# LEF file generated by Abstract Generator version 5.5.10 on Jul 30 14:47:58 2004
#
# Contains LEF for all bins.
# Options:   [x] Antenna
#            [x] Geometry
#            [x] Technology
VERSION 5.4 ;
NAMESCASESENSITIVE ON ;
BUSBITCHARS "[]" ;
DIVIDERCHAR "/" ;
UNITS
  DATABASE MICRONS 1000 ;
END UNITS

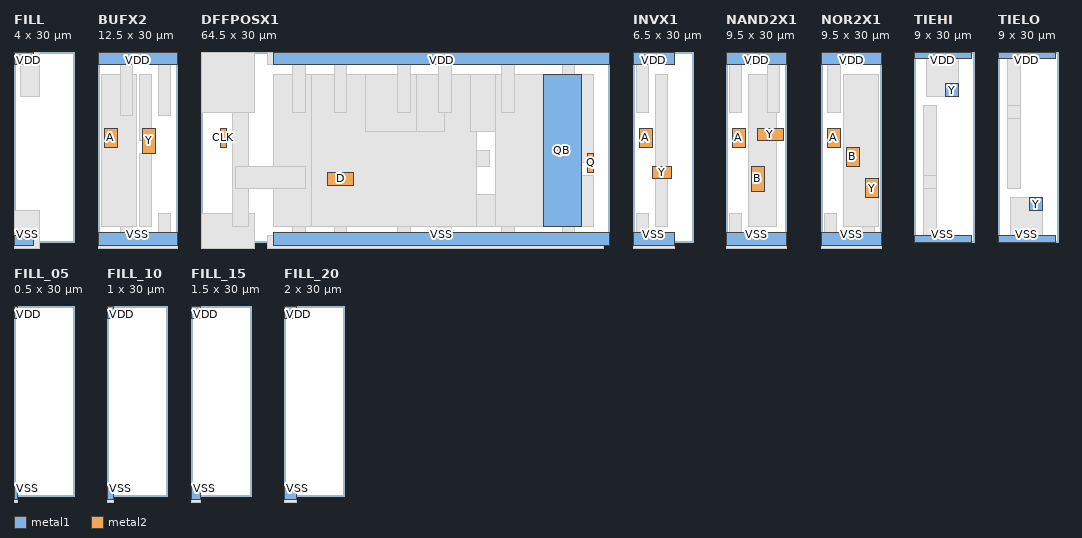
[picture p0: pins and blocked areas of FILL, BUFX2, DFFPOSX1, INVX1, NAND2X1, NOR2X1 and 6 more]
MACRO FILL
  CLASS CORE ;
  SOURCE USER ;
  ORIGIN 0 0 ;
  SIZE 4.0 BY 30.000 ;
  SYMMETRY Y ;
  SITE unit ;

  PIN VDD    DIRECTION INOUT ;
    USE POWER ;
    PORT
      LAYER metal1 ;
        RECT 0 28 3 30 ;
    END
  END VDD
  PIN VSS    DIRECTION INOUT ;
    USE GROUND ;
    PORT
      LAYER metal1 ;
        RECT 0 -0.5 3 1 ;
    END
  END VSS
  OBS
      LAYER metal1 ;
        RECT 0 -1 4 5 ;
        RECT 1 23 4 30 ;
  END
END FILL

MACRO BUFX2
  CLASS CORE ;
  SOURCE USER ;
  ORIGIN 0 0 ;
  SIZE 12.5 BY 30.000 ;
  SYMMETRY Y ;
  SITE unit ;

  PIN VDD    DIRECTION INOUT ;
    USE POWER ;
    PORT
      LAYER metal1 ;
        RECT 0.000 28.000 12.500 30.000 ;
    END
  END VDD
  PIN VSS    DIRECTION INOUT ;
    USE GROUND ;
    PORT
      LAYER metal1 ;
        RECT 0.000 -0.500 12.500 1.500 ;
    END
  END VSS
  PIN A    DIRECTION INPUT ;
    USE SIGNAL ;
    PORT
      LAYER metal2 ;
        RECT 1.000 15.000 3.000 18.000 ;
    END
  END A
  PIN Y    DIRECTION OUTPUT ;
    USE SIGNAL ;
    PORT
      LAYER metal2 ;
        RECT 7.000 14.000 9.000 18.000 ;
    END
  END Y
  OBS
      LAYER metal1 ;
        RECT 0 -1 12.5 1 ;
        RECT 3.5 1.5 5.5 4.5 ;
        RECT 9.5 1.5 11.5 4.5 ;
        RECT 6.5 2.5 8.5 14 ;
        RECT 0.5 2.5 6 26.5 ;
        RECT 6.5 16 8.5 26.5 ;
        RECT 3.5 20 5.5 28 ;
        RECT 9.5 20 11.5 28 ;
  END
END BUFX2

MACRO DFFPOSX1
  CLASS CORE ;
  SOURCE USER ;
  ORIGIN 0 0 ;
  SIZE 64.5 BY 30.000 ;
  SYMMETRY Y ;
  SITE unit ;

  PIN VDD    DIRECTION INOUT ;
    USE POWER ;
    PORT
      LAYER metal1 ;
        RECT 11.500 28.000 64.500 30.000 ;
    END
  END VDD
  PIN VSS    DIRECTION INOUT ;
    USE GROUND ;
    PORT
      LAYER metal1 ;
        RECT 11.500 -0.500 64.500 1.500 ;
    END
  END VSS
  PIN CLK    DIRECTION INPUT ;
    USE SIGNAL ;
    PORT
      LAYER metal2 ;
        RECT 3.000 15.000 4.000 18.000 ;
    END
  END CLK
  PIN D    DIRECTION INPUT ;
    USE SIGNAL ;
    PORT
      LAYER metal2 ;
        RECT 20.000 9.000 24.000 11.000 ;
    END
  END D
  PIN Q    DIRECTION OUTPUT ;
    USE SIGNAL ;
    PORT
      LAYER metal2 ;
        RECT 61.000 11.000 62.000 14.000 ;
    END
  END Q
  PIN QB
    DIRECTION OUTPUT ;
    USE SIGNAL ;
    PORT
      LAYER metal1 ;
        RECT 54.000 2.5 60.000 26.5 ;
    END
  END QB
  OBS
      LAYER metal1 ;
        RECT 10.5 -1 63.5 1 ;
        RECT 57 1.5 59 2.5 ;
        RECT 0 -1 8.5 4.5 ;
        RECT 14.5 1.5 16.5 4.5 ;
        RECT 21 1.5 23 4.5 ;
        RECT 31 1.5 33 4.5 ;
        RECT 37.5 1.5 39.5 4.5 ;
        RECT 47.5 1.5 49.5 4.5 ;
        RECT 30 2.5 38.5 7.5 ;
        RECT 42.5 2.5 50.5 7.5 ;
        RECT 20.5 9.5 22 10.5 ;
        RECT 60 2.5 62 10.5 ;
        RECT 14.5 8.5 16.5 11 ;
        RECT 26 2.5 34 11 ;
        RECT 20 12 45.5 14.5 ;
        RECT 3 16.5 4 18 ;
        RECT 5 2.5 7.5 26.5 ;
        RECT 11.5 2.5 17.5 26.5 ;
        RECT 17.5 2.5 43.5 26.5 ;
        RECT 26 17.5 34 26.5 ;
        RECT 34 17.5 38.5 26.5 ;
        RECT 42.5 17.5 50.5 26.5 ;
        RECT 46.5 2.5 54 26.5 ;
        RECT 60 12.5 62 26.5 ;
        RECT 14.5 20.5 16.5 28 ;
        RECT 21 20.5 23 28 ;
        RECT 31 20.5 33 28 ;
        RECT 37.5 20.5 39.5 28 ;
        RECT 47.5 20.5 49.5 28 ;
        RECT 57 26.5 59 28 ;
        RECT 0 20.5 8.5 30 ;
        RECT 10.5 28 11.5 30 ;
      LAYER metal2 ;
        RECT 5.5 8.5 16.5 12 ;
  END
END DFFPOSX1

MACRO INVX1
  CLASS CORE ;
  SOURCE USER ;
  ORIGIN 0 0 ;
  SIZE 6.5 BY 30.000 ;
  SYMMETRY Y ;
  SITE unit ;

  PIN VDD    DIRECTION INOUT ;
    USE POWER ;
    PORT
      LAYER metal1 ;
        RECT 0.000 28.000 6.500 30.000 ;
    END
  END VDD
  PIN VSS    DIRECTION INOUT ;
    USE GROUND ;
    PORT
      LAYER metal1 ;
        RECT 0.000 -0.500 6.500 1.500 ;
    END
  END VSS
  PIN A    DIRECTION INPUT ;
    USE SIGNAL ;
    PORT
      LAYER metal2 ;
        RECT 1.000 15.000 3.000 18.000 ;
    END
  END A
  PIN Y    DIRECTION OUTPUT ;
    USE SIGNAL ;
    PORT
      LAYER metal2 ;
        RECT 3.000 10.000 6.000 12.000 ;
    END
  END Y
  OBS
      LAYER metal1 ;
        RECT 0 -1 6.5 1 ;
        RECT 0.5 1.5 2.5 4.5 ;
        RECT 1.5 16.5 2.5 18 ;
        RECT 3.5 2.5 5.5 26.5 ;
        RECT 0.5 20.5 2.5 28 ;
  END
END INVX1

MACRO NAND2X1
  CLASS CORE ;
  SOURCE USER ;
  ORIGIN 0 0 ;
  SIZE 9.5 BY 30.000 ;
  SYMMETRY Y ;
  SITE unit ;

  PIN VDD    DIRECTION INOUT ;
    USE POWER ;
    PORT
      LAYER metal1 ;
        RECT 0.000 28.000 9.500 30.000 ;
    END
  END VDD
  PIN VSS    DIRECTION INOUT ;
    USE GROUND ;
    PORT
      LAYER metal1 ;
        RECT 0.000 -0.500 9.500 1.500 ;
    END
  END VSS
  PIN A    DIRECTION INPUT ;
    USE SIGNAL ;
    PORT
      LAYER metal2 ;
        RECT 1.000 15.000 3.000 18.000 ;
    END
  END A
  PIN B    DIRECTION INPUT ;
    USE SIGNAL ;
    PORT
      LAYER metal2 ;
        RECT 4.000 8.000 6.000 12.000 ;
    END
  END B
  PIN Y    DIRECTION OUTPUT ;
    USE SIGNAL ;
    PORT
      LAYER metal2 ;
        RECT 5.000 16.000 9.000 18.000 ;
    END
  END Y
  OBS
      LAYER metal1 ;
        RECT 0 -1 9.5 1 ;
        RECT 0.5 1.5 2.5 4.5 ;
        RECT 4.5 10 5.5 11.5 ;
        RECT 1.5 15 2.5 16.5 ;
        RECT 3.5 2.5 8 26.5 ;
        RECT 0.5 20.5 2.5 28 ;
        RECT 6.5 20.5 8.5 28 ;
  END
END NAND2X1

MACRO dcont
  CLASS CORE ;
END dcont

MACRO nsubcont
  CLASS CORE ;
END nsubcont

MACRO pcont
  CLASS CORE ;
END pcont

MACRO psubcont
  CLASS CORE ;
END psubcont


MACRO NOR2X1
  CLASS CORE ;
  SOURCE USER ;
  ORIGIN 0 0 ;
  SIZE 9.5 BY 30.000 ;
  SYMMETRY Y ;
  SITE unit ;

  PIN VDD    DIRECTION INOUT ;
    USE POWER ;
    PORT
      LAYER metal1 ;
        RECT 0.000 28.000 9.500 30.000 ;
    END
  END VDD
  PIN VSS    DIRECTION INOUT ;
    USE GROUND ;
    PORT
      LAYER metal1 ;
        RECT 0.000 -0.500 9.500 1.500 ;
    END
  END VSS
  PIN A    DIRECTION INPUT ;
    USE SIGNAL ;
    PORT
      LAYER metal2 ;
        RECT 1.000 15.000 3.000 18.000 ;
    END
  END A
  PIN B    DIRECTION INPUT ;
    USE SIGNAL ;
    PORT
      LAYER metal2 ;
        RECT 4.000 12.000 6.000 15.000 ;
    END
  END B
  PIN Y    DIRECTION OUTPUT ;
    USE SIGNAL ;
    PORT
      LAYER metal2 ;
        RECT 7.000 7.000 9.000 10.000 ;
    END
  END Y
  OBS
      LAYER metal1 ;
        RECT 0 -1 9.5 1 ;
        RECT 0.5 1.5 2.5 4.5 ;
        RECT 6.5 1.5 8.5 4.5 ;
        RECT 4.5 13.5 5.5 15 ;
        RECT 1.5 16.5 2.5 18 ;
        RECT 3.5 2.5 9 26.5 ;
        RECT 1 20.5 3 28 ;
  END
END NOR2X1


MACRO TIEHI
  CLASS CORE ;
  SOURCE USER ;
  ORIGIN 0 0 ;
  SIZE 9.000 BY 30.000 ;
  SYMMETRY Y ;
  SITE unit ;
  PIN VDD    DIRECTION INOUT ;
    USE POWER ;
    PORT
      LAYER metal1 ;
        RECT 0 29 9 30 ;
    END
  END VDD
  PIN VSS    DIRECTION INOUT ;
    USE GROUND ;
    PORT
      LAYER metal1 ;
        RECT 0 0 9 1 ;
    END
  END VSS
  PIN Y    DIRECTION OUTPUT ;
    USE SIGNAL ;
    PORT
      LAYER metal1 ;
        RECT 5 23 7 25 ;
    END
  END Y
  OBS
      LAYER metal1 ;
        RECT 1.5 1 3.5 21.5 ;
        RECT 2 23 7 29 ;
      LAYER metal2 ;
        RECT 1.5 8.5 3.5 10.5 ;
  END
END TIEHI

MACRO TIELO
  CLASS CORE ;
  SOURCE USER ;
  ORIGIN 0 0 ;
  SIZE 9.000 BY 30.000 ;
  SYMMETRY Y ;
  SITE unit ;
  PIN VDD    DIRECTION INOUT ;
    USE POWER ;
    PORT
      LAYER metal1 ;
        RECT 0 29 9 30 ;
    END
  END VDD
  PIN VSS    DIRECTION INOUT ;
    USE GROUND ;
    PORT
      LAYER metal1 ;
        RECT 0 0 9 1 ;
    END
  END VSS
  PIN Y    DIRECTION OUTPUT ;
    USE SIGNAL ;
    PORT
      LAYER metal1 ;
        RECT 5 5 7 7 ;
    END
  END Y
  OBS
      LAYER metal1 ;
        RECT 2 1 7 7 ;
        RECT 1.5 8.5 3.5 29 ;
      LAYER metal2 ;
        RECT 1.5 19.5 3.5 21.5 ;
  END
END TIELO


MACRO FILL_05
  CLASS CORE SPACER ;
  ORIGIN 0 0 ;
  SIZE 0.5 BY 30.000 ;
  SYMMETRY Y ;
  SITE unit ;
  PIN VDD    DIRECTION INOUT ;
    USE POWER ;
    PORT
      LAYER metal1 ;
        RECT 0.000 28.000 0.500 30.000 ;
    END
  END VDD
  PIN VSS    DIRECTION INOUT ;
    USE GROUND ;
    PORT
      LAYER metal1 ;
        RECT 0.000 -0.500 0.500 1.500 ;
    END
  END VSS

  OBS
      LAYER metal1 ;
        RECT 0 -1 0.5 1 ;
  END
END FILL_05

MACRO FILL_10
  CLASS CORE SPACER ;
  ORIGIN 0 0 ;
  SIZE 1.0 BY 30.000 ;
  SYMMETRY Y ;
  SITE unit ;
  PIN VDD    DIRECTION INOUT ;
    USE POWER ;
    PORT
      LAYER metal1 ;
        RECT 0.000 28.000 1.000 30.000 ;
    END
  END VDD
  PIN VSS    DIRECTION INOUT ;
    USE GROUND ;
    PORT
      LAYER metal1 ;
        RECT 0.000 -0.500 1.000 1.500 ;
    END
  END VSS

  OBS
      LAYER metal1 ;
        RECT 0 -1 1 1 ;
  END
END FILL_10

MACRO FILL_15
  CLASS CORE SPACER ;
  ORIGIN 0 0 ;
  SIZE 1.5 BY 30.000 ;
  SYMMETRY Y ;
  SITE unit ;
  PIN VDD    DIRECTION INOUT ;
    USE POWER ;
    PORT
      LAYER metal1 ;
        RECT 0.000 28.000 1.500 30.000 ;
    END
  END VDD
  PIN VSS    DIRECTION INOUT ;
    USE GROUND ;
    PORT
      LAYER metal1 ;
        RECT 0.000 -0.500 1.500 1.500 ;
    END
  END VSS

  OBS
      LAYER metal1 ;
        RECT 0 -1 1.5 1 ;
  END
END FILL_15

MACRO FILL_20
  CLASS CORE SPACER ;
  ORIGIN 0 0 ;
  SIZE 2.0 BY 30.000 ;
  SYMMETRY Y ;
  SITE unit ;
  PIN VDD    DIRECTION INOUT ;
    USE POWER ;
    PORT
      LAYER metal1 ;
        RECT 0.000 28.000 2.000 30.000 ;
    END
  END VDD
  PIN VSS    DIRECTION INOUT ;
    USE GROUND ;
    PORT
      LAYER metal1 ;
        RECT 0.000 -0.500 2.000 1.500 ;
    END
  END VSS

  OBS
      LAYER metal1 ;
        RECT 0 -1 2 1 ;
  END
END FILL_20

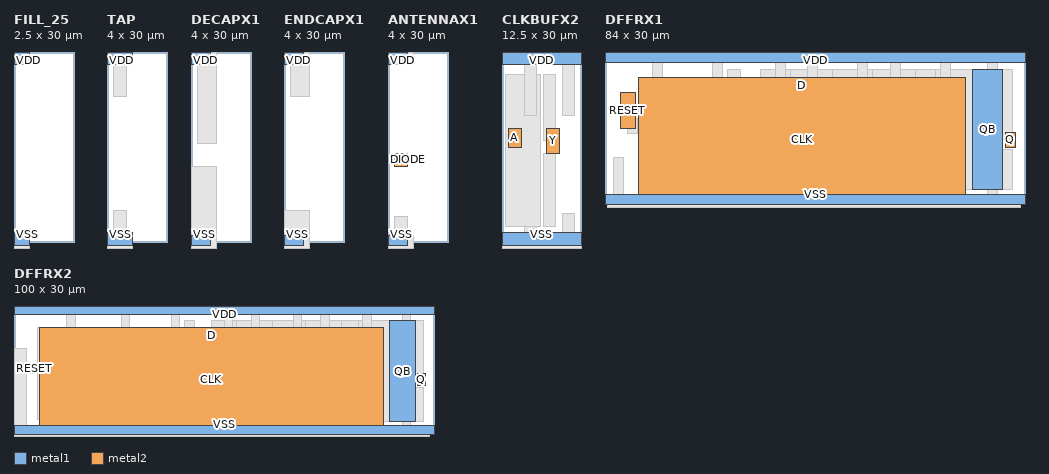
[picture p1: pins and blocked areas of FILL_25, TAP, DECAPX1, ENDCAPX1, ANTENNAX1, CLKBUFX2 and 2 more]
MACRO FILL_25
  CLASS CORE SPACER ;
  ORIGIN 0 0 ;
  SIZE 2.5 BY 30.000 ;
  SYMMETRY Y ;
  SITE unit ;
  PIN VDD    DIRECTION INOUT ;
    USE POWER ;
    PORT
      LAYER metal1 ;
        RECT 0.000 28.000 2.500 30.000 ;
    END
  END VDD
  PIN VSS    DIRECTION INOUT ;
    USE GROUND ;
    PORT
      LAYER metal1 ;
        RECT 0.000 -0.500 2.500 1.500 ;
    END
  END VSS

  OBS
      LAYER metal1 ;
        RECT 0 -1 2.5 1 ;
  END
END FILL_25

MACRO TAP
  CLASS CORE SPACER ;
  ORIGIN 0 0 ;
  SIZE 4.0 BY 30.000 ;
  SYMMETRY Y ;
  SITE unit ;
  PIN VDD    DIRECTION INOUT ;
    USE POWER ;
    PORT
      LAYER metal1 ;
        RECT 0.000 28.000 4.000 30.000 ;
    END
  END VDD
  PIN VSS    DIRECTION INOUT ;
    USE GROUND ;
    PORT
      LAYER metal1 ;
        RECT 0.000 -0.500 4.000 1.500 ;
    END
  END VSS

  OBS
      LAYER metal1 ;
        RECT 0 -1 4 1 ;
        RECT 1 1.5 3 5 ;
        RECT 1 23 3 28 ;
  END
END TAP
MACRO DECAPX1
  CLASS CORE ;
  SOURCE USER ;
  ORIGIN 0 0 ;
  SIZE 4.0 BY 30.000 ;
  SYMMETRY Y ;
  SITE unit ;

  PIN VDD    DIRECTION INOUT ;
    USE POWER ;
    PORT
      LAYER metal1 ;
        RECT 0 28 3 30 ;
    END
  END VDD
  PIN VSS    DIRECTION INOUT ;
    USE GROUND ;
    PORT
      LAYER metal1 ;
        RECT 0 -0.5 3 1 ;
    END
  END VSS
  OBS
      LAYER metal1 ;
        RECT 0 -1 4 12 ;
        RECT 1 15.5 4 30 ;
  END
END DECAPX1

MACRO ENDCAPX1
  CLASS CORE SPACER ;
  SOURCE USER ;
  ORIGIN 0 0 ;
  SIZE 4.0 BY 30.000 ;
  SYMMETRY Y ;
  SITE unit ;

  PIN VDD    DIRECTION INOUT ;
    USE POWER ;
    PORT
      LAYER metal1 ;
        RECT 0 28 3 30 ;
    END
  END VDD
  PIN VSS    DIRECTION INOUT ;
    USE GROUND ;
    PORT
      LAYER metal1 ;
        RECT 0 -0.5 3 1 ;
    END
  END VSS
  OBS
      LAYER metal1 ;
        RECT 0 -1 4 5 ;
        RECT 1 23 4 30 ;
  END
END ENDCAPX1

MACRO ANTENNAX1
  CLASS CORE ;
  SOURCE USER ;
  ORIGIN 0 0 ;
  SIZE 4.0 BY 30.000 ;
  SYMMETRY Y ;
  SITE unit ;

  PIN VDD    DIRECTION INOUT ;
    USE POWER ;
    PORT
      LAYER metal1 ;
        RECT 0 28 3 30 ;
    END
  END VDD
  PIN VSS    DIRECTION INOUT ;
    USE GROUND ;
    PORT
      LAYER metal1 ;
        RECT 0 -0.5 3 1 ;
    END
  END VSS
  PIN DIODE    DIRECTION INOUT ;
    USE SIGNAL ;
    PORT
      LAYER metal2 ;
        RECT 1.000 12.000 3.000 14.000 ;
    END
  END DIODE
  OBS
      LAYER metal1 ;
        RECT 0 -1 4 1 ;
        RECT 1 2 3 4 ;
        RECT 3 28 4 30 ;
  END
END ANTENNAX1

MACRO CLKBUFX2
  CLASS CORE ;
  SOURCE USER ;
  ORIGIN 0 0 ;
  SIZE 12.5 BY 30.000 ;
  SYMMETRY Y ;
  SITE unit ;

  PIN VDD    DIRECTION INOUT ;
    USE POWER ;
    PORT
      LAYER metal1 ;
        RECT 0.000 28.000 12.500 30.000 ;
    END
  END VDD
  PIN VSS    DIRECTION INOUT ;
    USE GROUND ;
    PORT
      LAYER metal1 ;
        RECT 0.000 -0.500 12.500 1.500 ;
    END
  END VSS
  PIN A    DIRECTION INPUT ;
    USE SIGNAL ;
    PORT
      LAYER metal2 ;
        RECT 1.000 15.000 3.000 18.000 ;
    END
  END A
  PIN Y    DIRECTION OUTPUT ;
    USE SIGNAL ;
    PORT
      LAYER metal2 ;
        RECT 7.000 14.000 9.000 18.000 ;
    END
  END Y
  OBS
      LAYER metal1 ;
        RECT 0 -1 12.5 1 ;
        RECT 3.5 1.5 5.5 4.5 ;
        RECT 9.5 1.5 11.5 4.5 ;
        RECT 6.5 2.5 8.5 14 ;
        RECT 0.5 2.5 6 26.5 ;
        RECT 6.5 16 8.5 26.5 ;
        RECT 3.5 20 5.5 28 ;
        RECT 9.5 20 11.5 28 ;
  END
END CLKBUFX2

MACRO DFFRX1
  CLASS CORE ;
  SOURCE USER ;
  ORIGIN 0 0 ;
  SIZE 84 BY 30.000 ;
  SYMMETRY Y ;
  SITE unit ;

  PIN VDD    DIRECTION INOUT ;
    USE POWER ;
    PORT
      LAYER metal1 ;
        RECT 0 28 84 30 ;
    END
  END VDD
  PIN VSS    DIRECTION INOUT ;
    USE GROUND ;
    PORT
      LAYER metal1 ;
        RECT 0 -0.5 84 1.5 ;
    END
  END VSS
  PIN CLK    DIRECTION INPUT ;
    USE SIGNAL ;
    PORT
      LAYER metal2 ;
        RECT 6.750 0.200 72.000 25.000 ;
    END
  END CLK
  PIN D    DIRECTION INPUT ;
    USE SIGNAL ;
    PORT
      LAYER metal2 ;
        RECT 6.750 0.200 72.000 25.000 ;
    END
  END D
  PIN RESET    DIRECTION INPUT ;
    USE SIGNAL ;
    PORT
      LAYER metal2 ;
        RECT 3.000 14.700 6.000 22.000 ;
    END
  END RESET
  PIN Q    DIRECTION OUTPUT ;
    USE SIGNAL ;
    PORT
      LAYER metal2 ;
        RECT 80.000 11.000 82.000 14.000 ;
    END
  END Q
  PIN QB    DIRECTION OUTPUT ;
    USE SIGNAL ;
    PORT
      LAYER metal1 ;
        RECT 73.5 2.5 79.5 26.5 ;
    END
  END QB
  OBS
      LAYER metal1 ;
        RECT 0.5 -1 83 -0.5 ;
        RECT 76.5 1.5 78.5 2.5 ;
        RECT 21.5 1.5 23.5 4.5 ;
        RECT 34 1.5 36 4.5 ;
        RECT 40.5 1.5 42.5 4.5 ;
        RECT 50.5 1.5 52.5 4.5 ;
        RECT 57 1.5 59 4.5 ;
        RECT 67 1.5 69 4.5 ;
        RECT 49.5 2.5 58 7.5 ;
        RECT 62 2.5 70 7.5 ;
        RECT 1.75 1.5 3.75 9 ;
        RECT 6.75 6 8.75 9 ;
        RECT 11.75 1.5 13.75 9 ;
        RECT 16.75 6 18.75 9 ;
        RECT 40 9.5 41.5 10.5 ;
        RECT 79.5 2.5 81.5 10.5 ;
        RECT 34 8.5 36 11 ;
        RECT 45.5 2.5 53.5 11 ;
        RECT 39.5 12 65 14.5 ;
        RECT 4.5 13.7 6.5 16.7 ;
        RECT 22.5 16.5 23.5 18 ;
        RECT 14 19 16 21 ;
        RECT 24.5 2.5 27 26.5 ;
        RECT 31 2.5 37 26.5 ;
        RECT 37 2.5 63 26.5 ;
        RECT 45.5 17.5 53.5 26.5 ;
        RECT 53.5 17.5 58 26.5 ;
        RECT 62 17.5 70 26.5 ;
        RECT 66 2.5 73.5 26.5 ;
        RECT 79.5 12.5 81.5 26.5 ;
        RECT 9.5 19 11.5 28 ;
        RECT 21.5 20.5 23.5 28 ;
        RECT 34 20.5 36 28 ;
        RECT 40.5 20.5 42.5 28 ;
        RECT 50.5 20.5 52.5 28 ;
        RECT 57 20.5 59 28 ;
        RECT 67 20.5 69 28 ;
        RECT 76.5 26.5 78.5 28 ;
      LAYER metal2 ;
        RECT 70.5 1.5 71.5 3 ;
        RECT 16.75 1.5 18.75 8 ;
        RECT 24.5 8.5 36 12 ;
        RECT 56 17.5 58 19.5 ;
        RECT 14 19 16 21 ;
        RECT 6.75 3 47 25 ;
  END
END DFFRX1

MACRO DFFRX2
  CLASS CORE ;
  SOURCE USER ;
  ORIGIN 0 0 ;
  SIZE 100 BY 30.000 ;
  SYMMETRY Y ;
  SITE unit ;

  PIN VDD    DIRECTION INOUT ;
    USE POWER ;
    PORT
      LAYER metal1 ;
        RECT 0 28 100.000 30 ;
    END
  END VDD
  PIN VSS    DIRECTION INOUT ;
    USE GROUND ;
    PORT
      LAYER metal1 ;
        RECT 0 -0.5 100.000 1.5 ;
    END
  END VSS
  PIN CLK    DIRECTION INPUT ;
    USE SIGNAL ;
    PORT
      LAYER metal2 ;
        RECT 6.000 0.200 88.000 25.000 ;
    END
  END CLK
  PIN D    DIRECTION INPUT ;
    USE SIGNAL ;
    PORT
      LAYER metal2 ;
        RECT 6.000 0.200 88.000 25.000 ;
    END
  END D
  PIN RESET    DIRECTION INPUT ;
    USE SIGNAL ;
    PORT
      LAYER metal2 ;
        RECT 2.000 13.900 4.000 16.300 ;
    END
  END RESET
  PIN Q    DIRECTION OUTPUT ;
    USE SIGNAL ;
    PORT
      LAYER metal2 ;
        RECT 96.000 11.000 98.000 14.000 ;
    END
  END Q
  PIN QB    DIRECTION OUTPUT ;
    USE SIGNAL ;
    PORT
      LAYER metal1 ;
        RECT 89.500 2.5 95.500 26.5 ;
    END
  END QB
  OBS
      LAYER metal1 ;
        RECT 0 -1 99 -0.5 ;
        RECT 92.5 1.5 94.5 2.5 ;
        RECT 37.5 1.5 39.5 4.5 ;
        RECT 50 1.5 52 4.5 ;
        RECT 56.5 1.5 58.5 4.5 ;
        RECT 66.5 1.5 68.5 4.5 ;
        RECT 73 1.5 75 4.5 ;
        RECT 83 1.5 85 4.5 ;
        RECT 65.5 2.5 74 7.5 ;
        RECT 78 2.5 86 7.5 ;
        RECT 17.75 1.5 19.75 9 ;
        RECT 22.75 6 24.75 9 ;
        RECT 27.75 1.5 29.75 9 ;
        RECT 32.75 6 34.75 9 ;
        RECT 56 9.5 57.5 10.5 ;
        RECT 95.5 2.5 97.5 10.5 ;
        RECT 50 8.5 52 11 ;
        RECT 61.5 2.5 69.5 11 ;
        RECT 55.5 12 81 14.5 ;
        RECT 2.5 13.9 4.5 16.3 ;
        RECT 20.5 13.7 22.5 16.7 ;
        RECT 38.5 16.5 39.5 18 ;
        RECT 16.6 18.2 18.2 19.8 ;
        RECT 0 1.5 3 20 ;
        RECT 5.5 17 7.5 20 ;
        RECT 30 19 32 21 ;
        RECT 40.5 2.5 43 26.5 ;
        RECT 47 2.5 53 26.5 ;
        RECT 53 2.5 79 26.5 ;
        RECT 61.5 17.5 69.5 26.5 ;
        RECT 69.5 17.5 74 26.5 ;
        RECT 78 17.5 86 26.5 ;
        RECT 82 2.5 89.5 26.5 ;
        RECT 95.5 12.5 97.5 26.5 ;
        RECT 12.6 18 14.6 28 ;
        RECT 25.5 19 27.5 28 ;
        RECT 37.5 20.5 39.5 28 ;
        RECT 50 20.5 52 28 ;
        RECT 56.5 20.5 58.5 28 ;
        RECT 66.5 20.5 68.5 28 ;
        RECT 73 20.5 75 28 ;
        RECT 83 20.5 85 28 ;
        RECT 92.5 26.5 94.5 28 ;
      LAYER metal2 ;
        RECT 86.5 1.5 87.5 3 ;
        RECT 32.75 1.5 34.75 8 ;
        RECT 40.5 8.5 52 12 ;
        RECT 2.5 13.9 4.5 16.3 ;
        RECT 72 17.5 74 19.5 ;
        RECT 30 19 32 21 ;
        RECT 5.5 3 63 25 ;
  END
END DFFRX2

END LIBRARY
